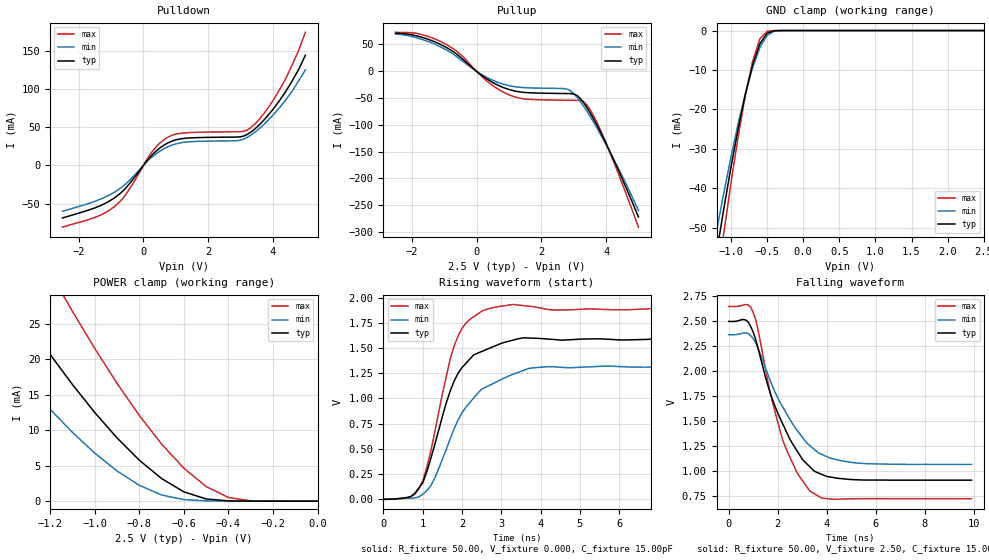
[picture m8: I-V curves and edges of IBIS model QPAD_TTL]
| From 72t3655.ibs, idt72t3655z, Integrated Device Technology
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|   Model QPAD_TTL
[Model]   QPAD_TTL
Model_type   3-state
Polarity   Non-Inverting
Enable   Active-High
Vmeas =  1.250V
C_comp   3.00pF   NA   NA
[Temperature Range]   25.00   85.00   -40.00
[Voltage Range]   2.50V   2.30V   2.70V
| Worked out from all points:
|   slope of the pulldown table from 0 to 0.375 V, typ, clamps not added: 20.8 ohm
|   slope of the pullup table from 0 to 0.375 V, typ, clamps not added: 22.8 ohm
|   GND clamp passes 1 mA (typ) near -0.51 V on its own axis
|   POWER clamp passes 1 mA (typ) near -0.57 V on its own axis
|   rising waveform, R_fixture 50.00, V_fixture 0.000, C_fixture 15.00pF: 20-80 % time 794ps typ, 1.04ns min, 648ps max; typ from 0 V to 1.58 V
|   falling waveform, R_fixture 50.00, V_fixture 2.50, C_fixture 15.00pF: 20-80 % time 1.47ns typ, 1.65ns min, 1.24ns max; typ from 2.5 V to 0.91 V
[Pulldown]
| voltage   I(typ)   I(min)   I(max)
-2.5V     -68.7mA    -59.9mA    -80.7mA
-1.5V     -55.54mA   -46.94mA   -68mA
-900mV    -42.65mA   -35.17mA   -54.12mA
-500mV    -27.42mA   -22.41mA   -35.32mA
300mV     15.04mA    12.19mA    19.67mA
800mV     30.27mA    25.19mA    37.94mA
2.9V      37.11mA    32.42mA    44.04mA
3.3V      43.01mA    39.08mA    48.93mA
3.7V      58.35mA    52.83mA    66.66mA
4.2V      84.6mA     75.39mA    98.7mA
4.6V      111mA      97.59mA    132mA
5V        144mA      125mA      174mA
[Pullup]
| voltage   I(typ)   I(min)   I(max)
-2.5V     70.79mA    69.58mA    72.7mA
-1.7V     63.76mA    59.86mA    68.67mA
-900mV    43.46mA    38.9mA     48.97mA
-500mV    26.48mA    22.2mA     31.66mA
200mV     -9.353mA   -7.544mA   -11.93mA
1.1V      -35.64mA   -28.02mA   -46.18mA
2.8V      -41.57mA   -33.39mA   -54.16mA
3.1V      -45.1mA    -48.25mA   -54.37mA
3.3V      -57.93mA   -64.46mA   -56.63mA
3.5V      -76.66mA   -83.4mA    -70.99mA
3.8V      -110mA     -115mA     -106mA
5V        -272mA     -260mA     -291mA
[GND_clamp]
| voltage   I(typ)   I(min)   I(max)
-2.5V     -221mA     -196mA     -255mA
-1.2V     -56.53mA   -50.9mA    -64.94mA
-1.1V     -45.3mA    -41.22mA   -51.5mA
-1V       -34.68mA   -32.07mA   -38.72mA
-900mV    -24.85mA   -23.59mA   -26.87mA
-800mV    -16.08mA   -15.96mA   -16.35mA
-700mV    -8.721mA   -9.411mA   -7.76mA
-600mV    -3.357mA   -4.326mA   -2.135mA
-500mV    -667uA     -1.241mA   -218uA
-400mV    -58.99uA   -179uA     -9.374uA
-300mV    -2.618uA   -14.77uA   -139nA
2.5V      25.05nA    49.28nA    24.82nA
[POWER_clamp]
| voltage   I(typ)   I(min)   I(max)
-2.5V     85.21mA    68.62mA    107mA
-1.6V     39.45mA    28.25mA    55.23mA
-1.4V     29.75mA    20.21mA    43.52mA
-1.3V     25.1mA     16.46mA    37.78mA
-1.2V     20.64mA    12.93mA    32.17mA
-1.1V     16.41mA    9.679mA    26.72mA
-800mV    5.767mA    2.226mA    12.07mA
-600mV    1.308mA    217uA      4.638mA
-500mV    308uA      38.03uA    2.054mA
-400mV    34.83uA    4.694uA    512uA
-300mV    2.145uA    415nA      47.35uA
0V        25.05nA    25.08nA    27nA
[Ramp]
| variable   typ   min   max
dV/dt_r   0.96/0.50n   0.79/0.60n   1.14/0.40n
dV/dt_f   0.96/0.93n   0.82/1.01n   1.14/0.82n
R_load = 50.00
[Rising Waveform]
R_fixture = 50.00
V_fixture = 0.000
C_fixture = 15.00pF
R_dut = 0.75
L_dut = 8.10nH
C_dut = 0.53pF
| time   V(typ)   V(min)   V(max)
0s        0V         0V         0V
700ps     28.41mV    10.64mV    27.58mV
900ps     111mV      23.69mV    103mV
1.2ns     396mV      130mV      469mV
1.7ns     1.074V     601mV      1.393V
1.8ns     1.172V     699mV      1.521V
2.1ns     1.348V     914mV      1.747V
2.5ns     1.465V     1.091V     1.864V
3.8ns     1.597V     1.303V     1.91V
9.9ns     1.585V     1.313V     1.885V
[Falling Waveform]
R_fixture = 50.00
V_fixture = 2.50
C_fixture = 15.00pF
R_dut = 0.75
L_dut = 8.10nH
C_dut = 0.53pF
| time   V(typ)   V(min)   V(max)
0s        2.5V       2.366V     2.65V
700ps     2.513V     2.385V     2.669V
1ns       2.393V     2.329V     2.589V
1.2ns     2.228V     2.229V     2.412V
1.7ns     1.778V     1.903V     1.774V
2.2ns     1.475V     1.643V     1.313V
2.8ns     1.198V     1.405V     979mV
3.3ns     1.046V     1.258V     803mV
5.2ns     914mV      1.082V     724mV
9.9ns     910mV      1.068V     724mV
